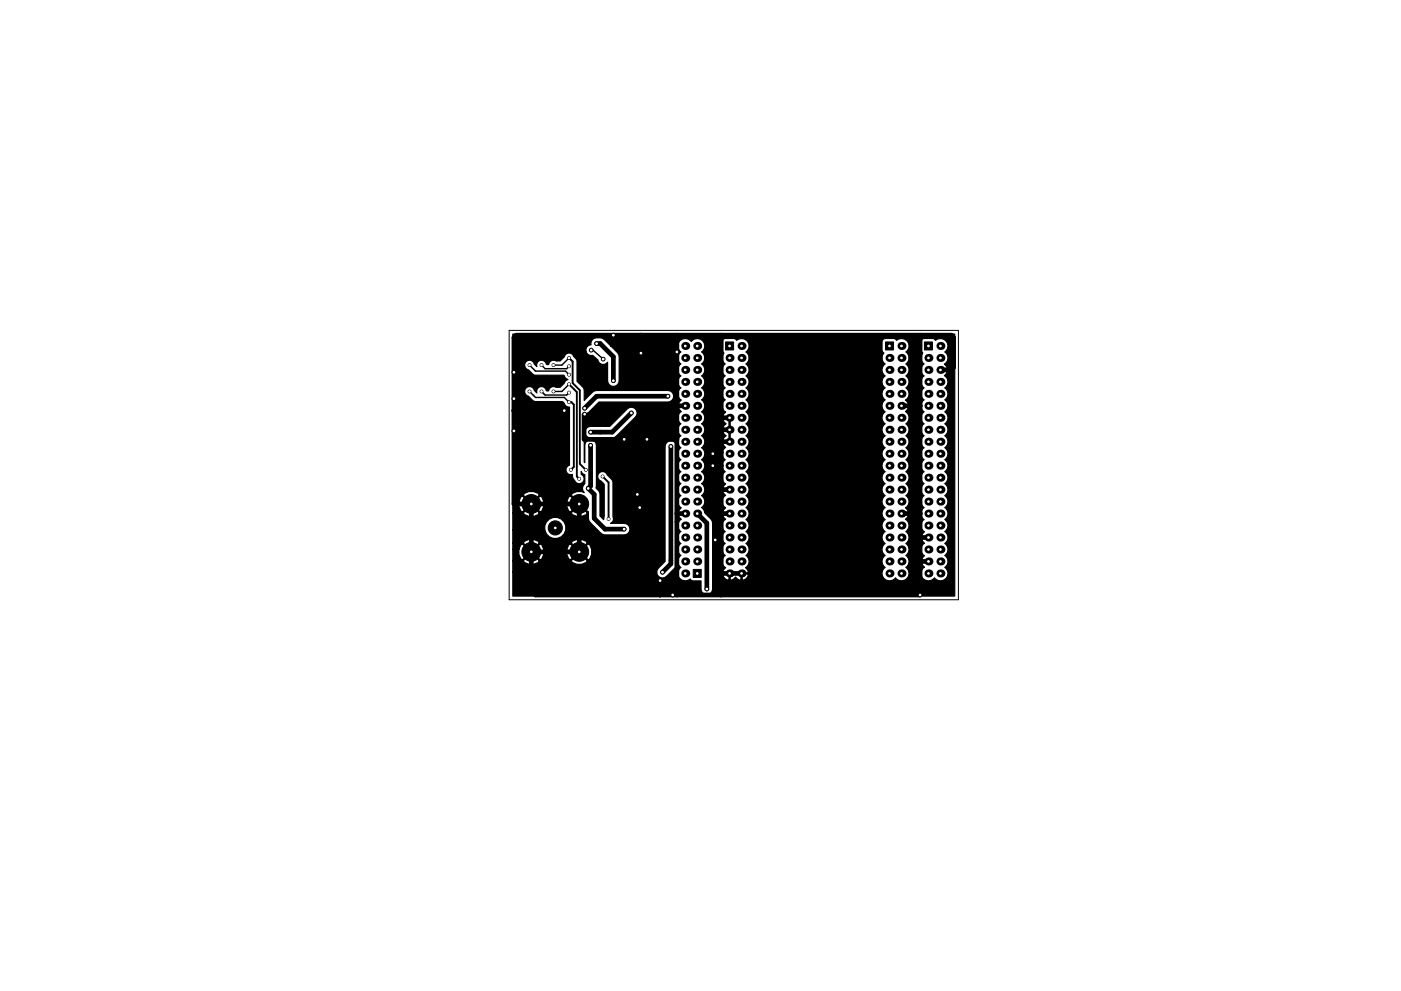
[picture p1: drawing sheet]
<svg xmlns="http://www.w3.org/2000/svg" width="297mm" height="210mm" viewBox="0 0 297 210" stroke-linecap="round" stroke-linejoin="round" font-family="sans-serif">
<path d="M107.9 70.1h95.3v57.1h-95.3z" fill="none" stroke="#000" stroke-width=".21"/>
<g fill="#000" stroke="#000" stroke-width=".21">
<path d="M153.8 72.6h1.7v1.7h-1.7zM187.7 72.6h1.7v1.7h-1.7zM196 72.6h1.7v1.7h-1.7zM147 120.8h1.7v1.7h-1.7z"/>
<circle cx="109" cy="79" r=".4"/>
<circle cx="112.3" cy="77.5" r=".3"/>
<circle cx="114.8" cy="77.5" r=".3"/>
<circle cx="117.3" cy="77.5" r=".3"/>
<circle cx="120.7" cy="79.5" r=".3"/>
<circle cx="120.7" cy="77.7" r=".3"/>
<circle cx="120.7" cy="75.9" r=".3"/>
<circle cx="125.3" cy="74.3" r=".4"/>
<circle cx="126.5" cy="72.9" r=".4"/>
<circle cx="127.9" cy="76.2" r=".4"/>
<circle cx="130" cy="71.1" r=".4"/>
<circle cx="135.9" cy="74.9" r=".4"/>
<circle cx="143.5" cy="74.7" r=".4"/>
<circle cx="109" cy="84.6" r=".4"/>
<circle cx="109" cy="91.4" r=".4"/>
<circle cx="112.3" cy="83.1" r=".3"/>
<circle cx="114.8" cy="83.1" r=".3"/>
<circle cx="117.3" cy="83.1" r=".3"/>
<circle cx="119.6" cy="87.1" r=".4"/>
<circle cx="120.7" cy="85.3" r=".3"/>
<circle cx="120.7" cy="81.5" r=".3"/>
<circle cx="120.7" cy="83.3" r=".3"/>
<circle cx="121" cy="99.7" r=".3"/>
<circle cx="124" cy="86.6" r=".4"/>
<circle cx="124" cy="87.9" r=".4"/>
<circle cx="124.2" cy="99.7" r=".3"/>
<circle cx="125.2" cy="94.5" r=".4"/>
<circle cx="125.2" cy="91.7" r=".4"/>
<circle cx="130" cy="80.8" r=".4"/>
<circle cx="132.3" cy="93.2" r=".4"/>
<circle cx="133.9" cy="87.6" r=".4"/>
<circle cx="137.2" cy="93.2" r=".4"/>
<circle cx="141.6" cy="84.1" r=".4"/>
<circle cx="142.2" cy="94.7" r=".4"/>
<circle cx="151.1" cy="96.3" r=".4"/>
<circle cx="151.1" cy="98.8" r=".4"/>
<circle cx="112.6" cy="106.9" r="2"/>
<circle cx="112.6" cy="117.1" r="2"/>
<circle cx="117.7" cy="112" r="1.5"/>
<circle cx="122.8" cy="106.9" r="2"/>
<circle cx="122.8" cy="117.1" r="2"/>
<circle cx="122.8" cy="101.6" r=".3"/>
<circle cx="124.7" cy="103.6" r=".4"/>
<circle cx="127.8" cy="101.1" r=".3"/>
<circle cx="129" cy="110.1" r=".3"/>
<circle cx="132.3" cy="112.3" r=".4"/>
<circle cx="135.1" cy="104.9" r=".4"/>
<circle cx="135.6" cy="107.7" r=".4"/>
<circle cx="151.6" cy="114.5" r=".4"/>
<circle cx="140" cy="123.2" r=".4"/>
<circle cx="140.5" cy="121.4" r=".4"/>
<circle cx="142.6" cy="126.2" r=".4"/>
<circle cx="149.9" cy="125" r=".4"/>
<circle cx="195.1" cy="126.2" r=".4"/>
</g>
<g fill="#000">
<circle cx="145.3" cy="78.5" r=".85"/>
<circle cx="145.3" cy="75.9" r=".85"/>
<circle cx="145.3" cy="73.4" r=".85"/>
<circle cx="147.8" cy="78.5" r=".85"/>
<circle cx="147.8" cy="73.4" r=".85"/>
<circle cx="147.8" cy="75.9" r=".85"/>
<circle cx="154.7" cy="78.5" r=".85"/>
<circle cx="154.7" cy="75.9" r=".85"/>
<circle cx="157.2" cy="78.5" r=".85"/>
<circle cx="157.2" cy="73.4" r=".85"/>
<circle cx="157.2" cy="75.9" r=".85"/>
<circle cx="188.6" cy="78.5" r=".85"/>
<circle cx="188.6" cy="75.9" r=".85"/>
<circle cx="191.1" cy="78.5" r=".85"/>
<circle cx="191.1" cy="73.4" r=".85"/>
<circle cx="191.1" cy="75.9" r=".85"/>
<circle cx="196.8" cy="78.5" r=".85"/>
<circle cx="196.8" cy="75.9" r=".85"/>
<circle cx="199.4" cy="73.4" r=".85"/>
<circle cx="199.4" cy="78.5" r=".85"/>
<circle cx="199.4" cy="75.9" r=".85"/>
<circle cx="145.3" cy="96.3" r=".85"/>
<circle cx="145.3" cy="88.6" r=".85"/>
<circle cx="145.3" cy="83.6" r=".85"/>
<circle cx="145.3" cy="81" r=".85"/>
<circle cx="145.3" cy="93.7" r=".85"/>
<circle cx="145.3" cy="86.1" r=".85"/>
<circle cx="145.3" cy="98.8" r=".85"/>
<circle cx="145.3" cy="91.2" r=".85"/>
<circle cx="147.8" cy="93.7" r=".85"/>
<circle cx="147.8" cy="88.6" r=".85"/>
<circle cx="147.8" cy="86.1" r=".85"/>
<circle cx="147.8" cy="96.3" r=".85"/>
<circle cx="147.8" cy="91.2" r=".85"/>
<circle cx="147.8" cy="81" r=".85"/>
<circle cx="147.8" cy="98.8" r=".85"/>
<circle cx="147.8" cy="83.6" r=".85"/>
<circle cx="154.7" cy="93.7" r=".85"/>
<circle cx="154.7" cy="96.3" r=".85"/>
<circle cx="154.7" cy="81" r=".85"/>
<circle cx="154.7" cy="86.1" r=".85"/>
<circle cx="154.7" cy="83.6" r=".85"/>
<circle cx="154.7" cy="91.2" r=".85"/>
<circle cx="154.7" cy="98.8" r=".85"/>
<circle cx="154.7" cy="88.6" r=".85"/>
<circle cx="157.2" cy="96.3" r=".85"/>
<circle cx="157.2" cy="93.7" r=".85"/>
<circle cx="157.2" cy="86.1" r=".85"/>
<circle cx="157.2" cy="81" r=".85"/>
<circle cx="157.2" cy="83.6" r=".85"/>
<circle cx="157.2" cy="88.6" r=".85"/>
<circle cx="157.2" cy="91.2" r=".85"/>
<circle cx="157.2" cy="98.8" r=".85"/>
<circle cx="188.6" cy="96.3" r=".85"/>
<circle cx="188.6" cy="88.6" r=".85"/>
<circle cx="188.6" cy="86.1" r=".85"/>
<circle cx="188.6" cy="93.7" r=".85"/>
<circle cx="188.6" cy="83.6" r=".85"/>
<circle cx="188.6" cy="91.2" r=".85"/>
<circle cx="188.6" cy="81" r=".85"/>
<circle cx="188.6" cy="98.8" r=".85"/>
<circle cx="191.1" cy="86.1" r=".85"/>
<circle cx="191.1" cy="83.6" r=".85"/>
<circle cx="191.1" cy="88.6" r=".85"/>
<circle cx="191.1" cy="91.2" r=".85"/>
<circle cx="191.1" cy="93.7" r=".85"/>
<circle cx="191.1" cy="96.3" r=".85"/>
<circle cx="191.1" cy="81" r=".85"/>
<circle cx="191.1" cy="98.8" r=".85"/>
<circle cx="196.8" cy="91.2" r=".85"/>
<circle cx="196.8" cy="86.1" r=".85"/>
<circle cx="196.8" cy="88.6" r=".85"/>
<circle cx="196.8" cy="93.7" r=".85"/>
<circle cx="196.8" cy="81" r=".85"/>
<circle cx="196.8" cy="83.6" r=".85"/>
<circle cx="196.8" cy="96.3" r=".85"/>
<circle cx="196.8" cy="98.8" r=".85"/>
<circle cx="199.4" cy="88.6" r=".85"/>
<circle cx="199.4" cy="83.6" r=".85"/>
<circle cx="199.4" cy="86.1" r=".85"/>
<circle cx="199.4" cy="91.2" r=".85"/>
<circle cx="199.4" cy="93.7" r=".85"/>
<circle cx="199.4" cy="96.3" r=".85"/>
<circle cx="199.4" cy="81" r=".85"/>
<circle cx="199.4" cy="98.8" r=".85"/>
<circle cx="145.3" cy="114" r=".85"/>
<circle cx="145.3" cy="119.1" r=".85"/>
<circle cx="145.3" cy="116.6" r=".85"/>
<circle cx="145.3" cy="109" r=".85"/>
<circle cx="145.3" cy="101.3" r=".85"/>
<circle cx="145.3" cy="111.5" r=".85"/>
<circle cx="145.3" cy="103.9" r=".85"/>
<circle cx="145.3" cy="106.4" r=".85"/>
<circle cx="147.8" cy="109" r=".85"/>
<circle cx="147.8" cy="116.6" r=".85"/>
<circle cx="147.8" cy="103.9" r=".85"/>
<circle cx="147.8" cy="119.1" r=".85"/>
<circle cx="147.8" cy="114" r=".85"/>
<circle cx="147.8" cy="111.5" r=".85"/>
<circle cx="147.8" cy="101.3" r=".85"/>
<circle cx="147.8" cy="106.4" r=".85"/>
<circle cx="154.7" cy="103.9" r=".85"/>
<circle cx="154.7" cy="109" r=".85"/>
<circle cx="154.7" cy="116.6" r=".85"/>
<circle cx="154.7" cy="119.1" r=".85"/>
<circle cx="154.7" cy="111.5" r=".85"/>
<circle cx="154.7" cy="114" r=".85"/>
<circle cx="154.7" cy="101.3" r=".85"/>
<circle cx="154.7" cy="106.4" r=".85"/>
<circle cx="157.2" cy="114" r=".85"/>
<circle cx="157.2" cy="119.1" r=".85"/>
<circle cx="157.2" cy="106.4" r=".85"/>
<circle cx="157.2" cy="111.5" r=".85"/>
<circle cx="157.2" cy="116.6" r=".85"/>
<circle cx="157.2" cy="101.3" r=".85"/>
<circle cx="157.2" cy="109" r=".85"/>
<circle cx="157.2" cy="103.9" r=".85"/>
<circle cx="188.6" cy="109" r=".85"/>
<circle cx="188.6" cy="116.6" r=".85"/>
<circle cx="188.6" cy="101.3" r=".85"/>
<circle cx="188.6" cy="103.9" r=".85"/>
<circle cx="188.6" cy="106.4" r=".85"/>
<circle cx="188.6" cy="111.5" r=".85"/>
<circle cx="188.6" cy="119.1" r=".85"/>
<circle cx="188.6" cy="114" r=".85"/>
<circle cx="191.1" cy="111.5" r=".85"/>
<circle cx="191.1" cy="109" r=".85"/>
<circle cx="191.1" cy="116.6" r=".85"/>
<circle cx="191.1" cy="101.3" r=".85"/>
<circle cx="191.1" cy="103.9" r=".85"/>
<circle cx="191.1" cy="106.4" r=".85"/>
<circle cx="191.1" cy="119.1" r=".85"/>
<circle cx="191.1" cy="114" r=".85"/>
<circle cx="196.8" cy="101.3" r=".85"/>
<circle cx="196.8" cy="109" r=".85"/>
<circle cx="196.8" cy="116.6" r=".85"/>
<circle cx="196.8" cy="103.9" r=".85"/>
<circle cx="196.8" cy="106.4" r=".85"/>
<circle cx="196.8" cy="111.5" r=".85"/>
<circle cx="196.8" cy="119.1" r=".85"/>
<circle cx="196.8" cy="114" r=".85"/>
<circle cx="199.4" cy="116.6" r=".85"/>
<circle cx="199.4" cy="101.3" r=".85"/>
<circle cx="199.4" cy="103.9" r=".85"/>
<circle cx="199.4" cy="106.4" r=".85"/>
<circle cx="199.4" cy="109" r=".85"/>
<circle cx="199.4" cy="114" r=".85"/>
<circle cx="199.4" cy="111.5" r=".85"/>
<circle cx="199.4" cy="119.1" r=".85"/>
<circle cx="145.3" cy="121.7" r=".85"/>
<circle cx="154.7" cy="121.7" r=".85"/>
<circle cx="157.2" cy="121.7" r=".85"/>
<circle cx="188.6" cy="121.7" r=".85"/>
<circle cx="191.1" cy="121.7" r=".85"/>
<circle cx="196.8" cy="121.7" r=".85"/>
<circle cx="199.4" cy="121.7" r=".85"/>
</g>
<g fill="none" stroke="#000" stroke-width="1">
<path d="M126.5 72.9h.8l2.7 2.8v5.1M135.9 71.1v3.8M143.5 71.1v55.1M152.9 71.1v55.1M195.1 71.1v55.1h-81.6l-.9-.9v-18.4M199.4 78.5h2.3l.5-.5v-6.4l-.5-.5h-92.2l-.5 .5v35.3h13.8v10.2h-10.2M109 87.1h10.6M124 87.9l-.2 .1v5.2h19.7M125.2 94.5v8.6l-.5 .5 1.3 1.3v5.1l2.3 2.3h4M133.9 87.6l-4.1 4.1h-4.6M141.6 84.1h-15.1l-2.5 2.5M142.2 94.7v24.9l-1.7 1.8"/>
<path d="M143.5 86.1h1.8M151.1 98.8h1.8M152.9 96h-1.5l-.3 .3M152.9 88.6h1.8M152.9 91.2h1.8M152.9 93.7h1.8M191.1 86.1h4M135.1 104.9l.5 .5v2.3M143.5 109h1.8M147.8 109l2.1 2v14M151.6 114.5h.5l.8 .8M152.9 109h1.8"/>
<path d="M152.9 103.9h1.8M191.1 109h4M195.1 114h1.7M195.1 119.1h1.7M140 123.2v3M152.9 121.7h4.3"/>
</g>
<path d="M112.3 77.5l1.2 1.2h6.4l.7 .8M114.8 77.5l.8 .7h4.5l.5-.5M120.6 75.9l-1.5 1.6h-1.8M125.3 74.3h.4l2.2 1.9M112.3 83.1l1.2 1.2h6.1l1 1M114.8 83.1l.8 .7h4.5l.5-.5M120.6 81.5l-1.5 1.6h-1.8" fill="none" stroke="#000" stroke-width=".3"/>
<path d="M120.6 75.9l.8 .8v4.6l1.5 1.5v15.6l1.3 1.3M120.6 81.5l1.7 1.7v17.9l.5 .5M120.6 85.3h.6l.5 .5v13.3l-.7 .6M127.8 101.1l1.2 1.3v7.7" fill="none" stroke="#000" stroke-width=".4"/>
<path d="M108.7 70.9h93.7v55.6h-93.7v-5.1h30.5l.1 .5a1.23 1.23 0 0 0 2 .4l1.8-1.8 .4-.9v-24.9a1.23 1.23 0 0 0-1.3-1.2 1.23 1.23 0 0 0-1.2 1.2v24.4l-1.4 1.4-.4 .9h-30.5v-2.4h2.3l.2 .3a2.29 2.29 0 0 0 3.1-.3h6.8l.2 .3a2.29 2.29 0 0 0 3.2-.3l-1.7-1.7-1.7 1.7h-6.8l-1.7-1.7-1.6 1.7h-2.3v-2.4h1.3v1l.4 1 .4 .2 1.7-1.7h.3l1.7 1.7 .4-.2 .4-1v-1h4.9v1l.4 1 .3 .2 1.7-1.7h.4l1.7 1.7a2.16 2.16 0 0 0 0-3.4l-1.7 1.7h-.4l-1.7-1.7-.3 .2-.4 1h-4.9l-.4-1-.4-.2-1.7 1.7h-.3l-1.7-1.7-.4 .2-.4 1h-1.3v-1.4h2.3l1.6 1.7 1.7-1.7h6.8l1.7 1.7 1.7-1.7a2.16 2.16 0 0 0-3.4 0h-6.8l-.2-.4a2.29 2.29 0 0 0-3.1 .4h-2.3v-2.8h6.8l.3 .9a2.27 2.27 0 0 0 3.8 0 2.27 2.27 0 0 0-1.4-3.5 2.27 2.27 0 0 0-2.7 2.6h-6.8v-3.6h2.3l.2 .4a2.29 2.29 0 0 0 3.1-.4h6.8l.2 .4a2.29 2.29 0 0 0 3.2-.4l-1.7-1.7-1.7 1.7h-6.8l-1.7-1.7-1.6 1.7h-2.3v-2.4h1.3v1.1l.4 .9 .4 .2 1.7-1.7h.3l1.7 1.7 .4-.2 .4-1v-1h4.9v1.1l.4 .9 .3 .2 1.7-1.7-1.7-1.7-.3 .3-.4 .9h-4.9l-.4-.9-.4-.3-1.7 1.7h-.3l-1.7-1.7-.4 .3-.4 .9h-1.3v-1.3h2.3l1.6 1.6 1.7-1.6-.2-.4a2.29 2.29 0 0 0-3.1 .4h-2.3v-27.4h2.5l.5 .6 .3 .2 1.2 1 6.3 .1 .3 .5 .6 .4-.6 .4-.2 .4-.8 .9-1.2-.2a1.03 1.03 0 0 0-1.3 .9l-.5-.1a1.04 1.04 0 0 0-1.3-.8 1.04 1.04 0 0 0-.7 1.4l-.5-.6a1.05 1.05 0 0 0-1.8-.5 1.05 1.05 0 0 0 .5 1.8l.9 .8 .6 .3h5.8l.3 .4a1.01 1.01 0 0 0 1.1 .8v12.3a1.03 1.03 0 0 0-.7 1.3 1.03 1.03 0 0 0 1.4 .7 2.1 2.1 0 0 0 1.2 1.9 1.04 1.04 0 0 0 1.2-.7 1.04 1.04 0 0 0-.6-1.2v-.7l.4 .6 .4 .1v1.9a1.25 1.25 0 0 0-.1 1.9 2.14 2.14 0 0 0-2.8 .6l3.7 3.5 .1 1.8 2.5 2.7 .9 .4h4a1.23 1.23 0 0 0 1.3-1.2 1.23 1.23 0 0 0-1.3-1.3h-2.8h.1a1.01 1.01 0 0 0 .4-1.3v-7.3l-.3-.7-1-1a1.03 1.03 0 0 0-1.7-.4 1.03 1.03 0 0 0 .4 1.8l.7 .6-.1 7.6-.8-.8v-4.6l-.1-.5-.7-.9v-9.5a1.23 1.23 0 0 0-1.4-.7 1.23 1.23 0 0 0-1 1.2v3.7l-.1-.2v-6.3h.1a1.23 1.23 0 0 0 1.2 1.2l5.1-.1 4.4-4.3a1.23 1.23 0 0 0 0-1.7 1.23 1.23 0 0 0-1.7 0l-3.7 3.7h-4.1a1.23 1.23 0 0 0-1.2 1.2h-.1v-3.9l.5-.1 .4-.2 2.2-2.2 15.1-.1a1.23 1.23 0 0 0 .7-1.4 1.23 1.23 0 0 0-1.2-1h-15.1l-.9 .4-1.7 1.8-.1-2.6-1.5-1.5v-4.2a1.33 1.33 0 0 0-.7-1.1 1.03 1.03 0 0 0-1-.7 1.03 1.03 0 0 0-1 .8l-.8 .9h-.9a1.03 1.03 0 0 0-1.6 .7l-.5-.1a1.04 1.04 0 0 0-1.3-.7 1.04 1.04 0 0 0-.7 1.3l-.7-.9a1.05 1.05 0 0 0-1.2-.4 1.05 1.05 0 0 0-.7 1.2h-2.5v-3.2h15.5l.2 .4a1.11 1.11 0 0 0 1.2 .5l1.2 1a1.14 1.14 0 0 0 .8 .9 1.14 1.14 0 0 0 1.2-.4l.1 4.3a1.23 1.23 0 0 0 1.4 .8 1.23 1.23 0 0 0 1-1.2l-.1-5.6-1.7-1.8h14.2l.1 .6 .6 .7-.3 .1a1.54 1.54 0 0 0 .3 2.4 1.51 1.51 0 0 0 0 2.6 1.51 1.51 0 0 0 0 2.5 1.51 1.51 0 0 0 .1 2.6l-.5 .4-.2 .4 .2 .3h1.4v.2h-1.4l-.2 .3 .2 .4 .5 .4-.4 .2a1.54 1.54 0 0 0 .3 2.4 1.51 1.51 0 0 0 0 2.6 1.51 1.51 0 0 0 0 2.5 1.51 1.51 0 0 0 0 2.5 1.51 1.51 0 0 0 0 2.6 1.51 1.51 0 0 0 0 2.5 1.51 1.51 0 0 0 0 2.6 1.51 1.51 0 0 0 .1 2.5l-.5 .5-.2 .4 .2 .2h1.4v.3h-1.4l-.2 .2 .2 .4 .5 .5-.4 .2a1.54 1.54 0 0 0 .3 2.4 1.51 1.51 0 0 0 0 2.5 1.51 1.51 0 0 0 0 2.6 1.51 1.51 0 0 0 0 2.5 1.57 1.57 0 0 0-.4 2.3 1.57 1.57 0 0 0 2.3 .1l.7 .5h1.6l.1 2.1a1.23 1.23 0 0 0 1.4 .8 1.23 1.23 0 0 0 1-1.2v-3h2.1a1.12 1.12 0 0 0 1.4 1v-1.2h.2v1.2l.2 .1 .6-.2 .4-.5 .3 .5 .6 .2 .2-.1v-1.2h.3v1.2a.99 .99 0 0 0 1.1-1.2h-5.1l-.2 .2h-2.1v-11l-.4-.9-1.3-1.3-.1-.4-.6-.7a1.51 1.51 0 0 0 0-2.5 1.51 1.51 0 0 0 0-2.6 1.51 1.51 0 0 0 0-2.5 1.51 1.51 0 0 0 0-2.6 1.51 1.51 0 0 0 0-2.5 1.51 1.51 0 0 0 0-2.5l.7-1h3.8l.2 .4 .6 .6-.6 .5-.2 .4 .2 .2h1.2v-2.3h-1.2l-.2 .2h-3.8a1.42 1.42 0 0 0-.7-1.6l.7-.9h3.8l.2 .4 .6 .5-.6 .5-.2 .4 .2 .3h1.2v-2.3h-1.2l-.2 .2h-3.8a1.42 1.42 0 0 0-.7-1.6 1.51 1.51 0 0 0 0-2.6 1.51 1.51 0 0 0 0-2.5 1.51 1.51 0 0 0 0-2.5 1.51 1.51 0 0 0 0-2.6l.6-.7 .1-.6h3.7l.1 .6 .6 .7-.3 .2a1.54 1.54 0 0 0 .3 2.4 1.51 1.51 0 0 0 0 2.5 1.51 1.51 0 0 0 0 2.5 1.51 1.51 0 0 0 .1 2.6l-.5 .5-.2 .4 .2 .2h1.4v5.3h-1.4l-.2 .3 .2 .4 .5 .4-.4 .2a1.54 1.54 0 0 0 .3 2.4 1.51 1.51 0 0 0 0 2.6 1.51 1.51 0 0 0 .1 2.6l-.5 .4-.2 .4 .2 .3 1.4-.1v.3h-1.4l-.2 .2 .2 .4 .5 .5-.4 .2a1.54 1.54 0 0 0 .4 2.4l-.5 .5-.2 .4 .2 .2h1.4v.3h-1.4l-.2 .2 .2 .4 .5 .5-.4 .2a1.54 1.54 0 0 0 .3 2.4 1.51 1.51 0 0 0 0 2.5 1.51 1.51 0 0 0 0 2.6 1.51 1.51 0 0 0 .1 2.5l-.5 .5-.2 .4 .2 .2h5.1l.2-.2-.2-.4-.4-.5 .3-.2a1.54 1.54 0 0 0-.3-2.3 1.51 1.51 0 0 0 0-2.6 1.51 1.51 0 0 0 0-2.5 1.51 1.51 0 0 0 0-2.6 1.51 1.51 0 0 0 0-2.5 1.51 1.51 0 0 0 0-2.5 1.51 1.51 0 0 0 0-2.6 1.51 1.51 0 0 0 0-2.5 1.51 1.51 0 0 0 0-2.6 1.51 1.51 0 0 0 0-2.5 1.51 1.51 0 0 0 0-2.5 1.51 1.51 0 0 0 0-2.6 1.51 1.51 0 0 0 0-2.5 1.51 1.51 0 0 0 0-2.6 1.51 1.51 0 0 0 0-2.5 1.51 1.51 0 0 0 0-2.5 1.51 1.51 0 0 0 0-2.6l.6-.7 .1-.6h28.2l.1 .6 .6 .7-.3 .2a1.54 1.54 0 0 0 .3 2.4 1.51 1.51 0 0 0 0 2.5 1.51 1.51 0 0 0 0 2.5 1.51 1.51 0 0 0 0 2.6 1.51 1.51 0 0 0 0 2.5 1.51 1.51 0 0 0 0 2.6 1.51 1.51 0 0 0 0 2.5 1.51 1.51 0 0 0 0 2.5 1.51 1.51 0 0 0 0 2.6 1.51 1.51 0 0 0 0 2.5 1.51 1.51 0 0 0 0 2.6 1.51 1.51 0 0 0 0 2.5 1.51 1.51 0 0 0 0 2.5 1.51 1.51 0 0 0 0 2.6 1.51 1.51 0 0 0 0 2.5 1.51 1.51 0 0 0 0 2.6 1.51 1.51 0 0 0 0 2.5 1.57 1.57 0 0 0-.2 2.4 1.57 1.57 0 0 0 2.4-.2 1.57 1.57 0 0 0 2.4 .2 1.57 1.57 0 0 0-.3-2.4 1.51 1.51 0 0 0 0-2.5 1.51 1.51 0 0 0 0-2.6 1.51 1.51 0 0 0 0-2.5 1.51 1.51 0 0 0 0-2.6l.4-.5 .2-.4-.1-.2h-1.5v-.3h1.5l.1-.2-.2-.4-.4-.5 .3-.2a1.54 1.54 0 0 0-.3-2.3 1.51 1.51 0 0 0 0-2.6 1.51 1.51 0 0 0 0-2.5 1.51 1.51 0 0 0 0-2.6 1.51 1.51 0 0 0 0-2.5 1.51 1.51 0 0 0 0-2.5 1.51 1.51 0 0 0 0-2.6 1.51 1.51 0 0 0 0-2.6l.4-.4 .2-.4-.1-.3h-1.5v-.2h1.5l.1-.3-.2-.4-.4-.4 .3-.2a1.54 1.54 0 0 0-.3-2.4 1.51 1.51 0 0 0 0-2.5 1.51 1.51 0 0 0 0-2.6l.6-.7 .1-.6h2.5l.2 .6 .5 .7-.2 .2a1.54 1.54 0 0 0 .2 2.4 1.51 1.51 0 0 0 0 2.5 1.51 1.51 0 0 0 0 2.5 1.51 1.51 0 0 0 0 2.6 1.51 1.51 0 0 0 0 2.5 1.51 1.51 0 0 0 0 2.6 1.51 1.51 0 0 0 0 2.5 1.51 1.51 0 0 0 0 2.5 1.51 1.51 0 0 0 0 2.6 1.51 1.51 0 0 0 0 2.5 1.51 1.51 0 0 0 0 2.6 1.51 1.51 0 0 0 0 2.5 1.51 1.51 0 0 0 0 2.5 1.51 1.51 0 0 0 .1 2.6l-.4 .5-.2 .4 .1 .2h1.5v.3h-1.5l-.1 .2 .2 .4 .4 .5-.3 .2a1.54 1.54 0 0 0 .3 2.4l-.4 .5-.2 .4 .1 .2h1.5v.2h-1.5l-.1 .3 .2 .4 .4 .4-.3 .2a1.59 1.59 0 0 0 .1 2.4 1.59 1.59 0 0 0 2.3-.3 1.57 1.57 0 0 0 2.4 .2 1.57 1.57 0 0 0-.2-2.4 1.51 1.51 0 0 0 0-2.5 1.51 1.51 0 0 0 0-2.6 1.51 1.51 0 0 0 0-2.5 1.51 1.51 0 0 0 0-2.6 1.51 1.51 0 0 0 0-2.5 1.51 1.51 0 0 0 0-2.5 1.51 1.51 0 0 0 0-2.6 1.51 1.51 0 0 0 0-2.5 1.51 1.51 0 0 0 0-2.6 1.51 1.51 0 0 0 0-2.5 1.51 1.51 0 0 0 0-2.5 1.51 1.51 0 0 0 0-2.6 1.51 1.51 0 0 0 0-2.5 1.51 1.51 0 0 0 0-2.6 1.51 1.51 0 0 0 0-2.5 1.51 1.51 0 0 0-.1-2.6l.5-.5 .1-.4-.1-.2h-1.4l-.1-.2h1.5l.1-.3-.1-.4-.5-.4 .3-.2a1.54 1.54 0 0 0-.2-2.4 1.57 1.57 0 0 0 .3-2.3 1.57 1.57 0 0 0-2.3-.2l-.6-.4h-1.7a.74 .74 0 0 0-.7 .8v1.7l.4 .6-.3 .4-.2 .6h-2.5l-.1-.6-.6-.6a1.57 1.57 0 0 0 .4-2.3 1.57 1.57 0 0 0-2.3-.2l-.7-.4h-1.7a.74 .74 0 0 0-.7 .8v1.7l.4 .6-.3 .4-.1 .6h-28.2l-.1-.6-.6-.6a1.57 1.57 0 0 0 .4-2.3 1.57 1.57 0 0 0-2.3-.2l-.7-.4h-1.7a.74 .74 0 0 0-.7 .8v1.7l.4 .6-.3 .4-.1 .6h-3.7l-.1-.6-.6-.6a1.57 1.57 0 0 0 .3-2.4 1.57 1.57 0 0 0-2.4 .2 1.59 1.59 0 0 0-1.8-.6 1.59 1.59 0 0 0-1.1 1.5h-14.2l-1.4-1.4a2 2 0 0 0-2.7 .4l-.1 .8a1.11 1.11 0 0 0-1.1 1.3h-15.5z" fill="#000" stroke="#000" stroke-width=".25"/>
<g fill="#fff" stroke="#fff" stroke-width=".21">
<circle cx="142.6" cy="126.2" r=".17"/>
<circle cx="195.1" cy="126.2" r=".17"/>
<circle cx="151.6" cy="114.5" r=".17"/>
<circle cx="151.1" cy="98.8" r=".17"/>
<circle cx="151.1" cy="96.3" r=".17"/>
<circle cx="124" cy="87.9" r=".17"/>
<circle cx="143.5" cy="74.7" r=".17"/>
<circle cx="119.6" cy="87.1" r=".17"/>
<circle cx="137.2" cy="93.2" r=".17"/>
<circle cx="132.3" cy="93.2" r=".17"/>
<circle cx="135.6" cy="107.7" r=".17"/>
<circle cx="135.1" cy="104.9" r=".17"/>
<circle cx="140" cy="123.2" r=".17"/>
<circle cx="109" cy="91.4" r=".17"/>
<circle cx="135.9" cy="74.9" r=".17"/>
<circle cx="130" cy="71.1" r=".17"/>
<circle cx="109" cy="79" r=".17"/>
<circle cx="109" cy="84.6" r=".17"/>
<circle cx="125.2" cy="94.5" r=".17"/>
<circle cx="125.2" cy="91.7" r=".17"/>
<circle cx="125.3" cy="74.3" r=".17"/>
<circle cx="127.9" cy="76.2" r=".17"/>
<circle cx="126.5" cy="72.9" r=".17"/>
<circle cx="130" cy="80.8" r=".17"/>
<circle cx="133.9" cy="87.6" r=".17"/>
<circle cx="124.7" cy="103.6" r=".17"/>
<circle cx="132.3" cy="112.3" r=".17"/>
<circle cx="124" cy="86.6" r=".17"/>
<circle cx="141.6" cy="84.1" r=".17"/>
<circle cx="140.5" cy="121.4" r=".17"/>
<circle cx="142.2" cy="94.7" r=".17"/>
<circle cx="122.8" cy="101.6" r=".17"/>
<circle cx="120.6" cy="81.5" r=".17"/>
<circle cx="117.3" cy="83.1" r=".17"/>
<circle cx="124.2" cy="99.7" r=".17"/>
<circle cx="120.6" cy="75.9" r=".17"/>
<circle cx="117.3" cy="77.5" r=".17"/>
<circle cx="149.9" cy="125" r=".17"/>
<circle cx="120.6" cy="79.5" r=".17"/>
<circle cx="112.3" cy="77.5" r=".17"/>
<circle cx="120.6" cy="77.7" r=".17"/>
<circle cx="114.8" cy="77.5" r=".17"/>
<circle cx="121" cy="99.7" r=".17"/>
<circle cx="112.3" cy="83.1" r=".17"/>
<circle cx="120.6" cy="85.3" r=".17"/>
<circle cx="120.6" cy="83.3" r=".17"/>
<circle cx="114.8" cy="83.1" r=".17"/>
<circle cx="129" cy="110.1" r=".17"/>
<circle cx="127.8" cy="101.1" r=".17"/>
<circle cx="147.8" cy="121.7" r=".17"/>
<circle cx="145.3" cy="121.7" r=".17"/>
<circle cx="147.8" cy="119.1" r=".17"/>
<circle cx="145.3" cy="119.1" r=".17"/>
<circle cx="147.8" cy="116.6" r=".17"/>
<circle cx="145.3" cy="116.6" r=".17"/>
<circle cx="147.8" cy="114" r=".17"/>
<circle cx="145.3" cy="114" r=".17"/>
<circle cx="147.8" cy="111.5" r=".17"/>
<circle cx="145.3" cy="111.5" r=".17"/>
<circle cx="147.8" cy="109" r=".17"/>
<circle cx="145.3" cy="109" r=".17"/>
<circle cx="147.8" cy="106.4" r=".17"/>
<circle cx="145.3" cy="106.4" r=".17"/>
<circle cx="147.8" cy="103.9" r=".17"/>
<circle cx="145.3" cy="103.9" r=".17"/>
<circle cx="147.8" cy="101.3" r=".17"/>
<circle cx="145.3" cy="101.3" r=".17"/>
<circle cx="147.8" cy="98.8" r=".17"/>
<circle cx="145.3" cy="98.8" r=".17"/>
<circle cx="147.8" cy="96.3" r=".17"/>
<circle cx="145.3" cy="96.3" r=".17"/>
<circle cx="147.8" cy="93.7" r=".17"/>
<circle cx="145.3" cy="93.7" r=".17"/>
<circle cx="147.8" cy="91.2" r=".17"/>
<circle cx="145.3" cy="91.2" r=".17"/>
<circle cx="147.8" cy="88.6" r=".17"/>
<circle cx="145.3" cy="88.6" r=".17"/>
<circle cx="147.8" cy="86.1" r=".17"/>
<circle cx="145.3" cy="86.1" r=".17"/>
<circle cx="147.8" cy="83.6" r=".17"/>
<circle cx="145.3" cy="83.6" r=".17"/>
<circle cx="147.8" cy="81" r=".17"/>
<circle cx="145.3" cy="81" r=".17"/>
<circle cx="147.8" cy="78.5" r=".17"/>
<circle cx="145.3" cy="78.5" r=".17"/>
<circle cx="147.8" cy="75.9" r=".17"/>
<circle cx="145.3" cy="75.9" r=".17"/>
<circle cx="147.8" cy="73.4" r=".17"/>
<circle cx="145.3" cy="73.4" r=".17"/>
<circle cx="117.7" cy="112" r=".17"/>
<circle cx="122.8" cy="117.1" r=".17"/>
<circle cx="112.6" cy="117.1" r=".17"/>
<circle cx="112.6" cy="106.9" r=".17"/>
<circle cx="122.8" cy="106.9" r=".17"/>
<circle cx="196.8" cy="73.4" r=".17"/>
<circle cx="199.4" cy="73.4" r=".17"/>
<circle cx="196.8" cy="75.9" r=".17"/>
<circle cx="199.4" cy="75.9" r=".17"/>
<circle cx="196.8" cy="78.5" r=".17"/>
<circle cx="199.4" cy="78.5" r=".17"/>
<circle cx="196.8" cy="81" r=".17"/>
<circle cx="199.4" cy="81" r=".17"/>
<circle cx="196.8" cy="83.6" r=".17"/>
<circle cx="199.4" cy="83.6" r=".17"/>
<circle cx="196.8" cy="86.1" r=".17"/>
<circle cx="199.4" cy="86.1" r=".17"/>
<circle cx="196.8" cy="88.6" r=".17"/>
<circle cx="199.4" cy="88.6" r=".17"/>
<circle cx="196.8" cy="91.2" r=".17"/>
<circle cx="199.4" cy="91.2" r=".17"/>
<circle cx="196.8" cy="93.7" r=".17"/>
<circle cx="199.4" cy="93.7" r=".17"/>
<circle cx="196.8" cy="96.3" r=".17"/>
<circle cx="199.4" cy="96.3" r=".17"/>
<circle cx="196.8" cy="98.8" r=".17"/>
<circle cx="199.4" cy="98.8" r=".17"/>
<circle cx="196.8" cy="101.3" r=".17"/>
<circle cx="199.4" cy="101.3" r=".17"/>
<circle cx="196.8" cy="103.9" r=".17"/>
<circle cx="199.4" cy="103.9" r=".17"/>
<circle cx="196.8" cy="106.4" r=".17"/>
<circle cx="199.4" cy="106.4" r=".17"/>
<circle cx="196.8" cy="109" r=".17"/>
<circle cx="199.4" cy="109" r=".17"/>
<circle cx="196.8" cy="111.5" r=".17"/>
<circle cx="199.4" cy="111.5" r=".17"/>
<circle cx="196.8" cy="114" r=".17"/>
<circle cx="199.4" cy="114" r=".17"/>
<circle cx="196.8" cy="116.6" r=".17"/>
<circle cx="199.4" cy="116.6" r=".17"/>
<circle cx="196.8" cy="119.1" r=".17"/>
<circle cx="199.4" cy="119.1" r=".17"/>
<circle cx="196.8" cy="121.7" r=".17"/>
<circle cx="199.4" cy="121.7" r=".17"/>
<circle cx="154.7" cy="73.4" r=".17"/>
<circle cx="157.2" cy="73.4" r=".17"/>
<circle cx="154.7" cy="75.9" r=".17"/>
<circle cx="157.2" cy="75.9" r=".17"/>
<circle cx="154.7" cy="78.5" r=".17"/>
<circle cx="157.2" cy="78.5" r=".17"/>
<circle cx="154.7" cy="81" r=".17"/>
<circle cx="157.2" cy="81" r=".17"/>
<circle cx="154.7" cy="83.6" r=".17"/>
<circle cx="157.2" cy="83.6" r=".17"/>
<circle cx="154.7" cy="86.1" r=".17"/>
<circle cx="157.2" cy="86.1" r=".17"/>
<circle cx="154.7" cy="88.6" r=".17"/>
<circle cx="157.2" cy="88.6" r=".17"/>
<circle cx="154.7" cy="91.2" r=".17"/>
<circle cx="157.2" cy="91.2" r=".17"/>
<circle cx="154.7" cy="93.7" r=".17"/>
<circle cx="157.2" cy="93.7" r=".17"/>
<circle cx="154.7" cy="96.3" r=".17"/>
<circle cx="157.2" cy="96.3" r=".17"/>
<circle cx="154.7" cy="98.8" r=".17"/>
<circle cx="157.2" cy="98.8" r=".17"/>
<circle cx="154.7" cy="101.3" r=".17"/>
<circle cx="157.2" cy="101.3" r=".17"/>
<circle cx="154.7" cy="103.9" r=".17"/>
<circle cx="157.2" cy="103.9" r=".17"/>
<circle cx="154.7" cy="106.4" r=".17"/>
<circle cx="157.2" cy="106.4" r=".17"/>
<circle cx="154.7" cy="109" r=".17"/>
<circle cx="157.2" cy="109" r=".17"/>
<circle cx="154.7" cy="111.5" r=".17"/>
<circle cx="157.2" cy="111.5" r=".17"/>
<circle cx="154.7" cy="114" r=".17"/>
<circle cx="157.2" cy="114" r=".17"/>
<circle cx="154.7" cy="116.6" r=".17"/>
<circle cx="157.2" cy="116.6" r=".17"/>
<circle cx="154.7" cy="119.1" r=".17"/>
<circle cx="157.2" cy="119.1" r=".17"/>
<circle cx="154.7" cy="121.7" r=".17"/>
<circle cx="157.2" cy="121.7" r=".17"/>
<circle cx="188.6" cy="73.4" r=".17"/>
<circle cx="191.1" cy="73.4" r=".17"/>
<circle cx="188.6" cy="75.9" r=".17"/>
<circle cx="191.1" cy="75.9" r=".17"/>
<circle cx="188.6" cy="78.5" r=".17"/>
<circle cx="191.1" cy="78.5" r=".17"/>
<circle cx="188.6" cy="81" r=".17"/>
<circle cx="191.1" cy="81" r=".17"/>
<circle cx="188.6" cy="83.6" r=".17"/>
<circle cx="191.1" cy="83.6" r=".17"/>
<circle cx="188.6" cy="86.1" r=".17"/>
<circle cx="191.1" cy="86.1" r=".17"/>
<circle cx="188.6" cy="88.6" r=".17"/>
<circle cx="191.1" cy="88.6" r=".17"/>
<circle cx="188.6" cy="91.2" r=".17"/>
<circle cx="191.1" cy="91.2" r=".17"/>
<circle cx="188.6" cy="93.7" r=".17"/>
<circle cx="191.1" cy="93.7" r=".17"/>
<circle cx="188.6" cy="96.3" r=".17"/>
<circle cx="191.1" cy="96.3" r=".17"/>
<circle cx="188.6" cy="98.8" r=".17"/>
<circle cx="191.1" cy="98.8" r=".17"/>
<circle cx="188.6" cy="101.3" r=".17"/>
<circle cx="191.1" cy="101.3" r=".17"/>
<circle cx="188.6" cy="103.9" r=".17"/>
<circle cx="191.1" cy="103.9" r=".17"/>
<circle cx="188.6" cy="106.4" r=".17"/>
<circle cx="191.1" cy="106.4" r=".17"/>
<circle cx="188.6" cy="109" r=".17"/>
<circle cx="191.1" cy="109" r=".17"/>
<circle cx="188.6" cy="111.5" r=".17"/>
<circle cx="191.1" cy="111.5" r=".17"/>
<circle cx="188.6" cy="114" r=".17"/>
<circle cx="191.1" cy="114" r=".17"/>
<circle cx="188.6" cy="116.6" r=".17"/>
<circle cx="191.1" cy="116.6" r=".17"/>
<circle cx="188.6" cy="119.1" r=".17"/>
<circle cx="191.1" cy="119.1" r=".17"/>
<circle cx="188.6" cy="121.7" r=".17"/>
<circle cx="191.1" cy="121.7" r=".17"/>
</g>
</svg>
